VERSION 5.7 ;
  NOWIREEXTENSIONATPIN ON ;
  DIVIDERCHAR "/" ;
  BUSBITCHARS "[]" ;
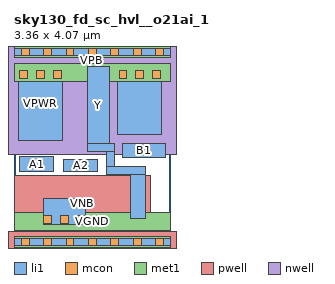
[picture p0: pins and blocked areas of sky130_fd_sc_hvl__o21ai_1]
MACRO sky130_fd_sc_hvl__o21ai_1
  CLASS BLOCK ;
  FOREIGN sky130_fd_sc_hvl__o21ai_1 ;
  ORIGIN 0.000 0.000 ;
  SIZE 3.360 BY 4.070 ;
  PIN A1
    ANTENNAGATEAREA 1.125000 ;
    PORT
      LAYER li1 ;
        RECT 0.125 1.505 0.855 1.835 ;
    END
  END A1
  PIN A2
    ANTENNAGATEAREA 1.125000 ;
    PORT
      LAYER li1 ;
        RECT 1.065 1.505 1.795 1.760 ;
    END
  END A2
  PIN B1
    ANTENNAGATEAREA 1.125000 ;
    PORT
      LAYER li1 ;
        RECT 2.325 1.805 3.235 2.120 ;
    END
  END B1
  PIN VGND
    USE GROUND ;
    PORT
      LAYER li1 ;
        RECT 0.640 0.365 1.530 0.925 ;
      LAYER mcon ;
        RECT 0.640 0.395 0.810 0.565 ;
        RECT 1.000 0.395 1.170 0.565 ;
        RECT 1.360 0.395 1.530 0.565 ;
      LAYER met1 ;
        RECT 0.000 0.255 3.360 0.625 ;
    END
  END VGND
  PIN VNB
    ANTENNADIFFAREA 0.571200 ;
    PORT
      LAYER pwell ;
        RECT 0.020 0.215 2.930 1.415 ;
        RECT -0.130 -0.215 3.490 0.215 ;
      LAYER li1 ;
        RECT 0.000 -0.085 3.360 0.085 ;
      LAYER mcon ;
        RECT 0.155 -0.085 0.325 0.085 ;
        RECT 0.635 -0.085 0.805 0.085 ;
        RECT 1.115 -0.085 1.285 0.085 ;
        RECT 1.595 -0.085 1.765 0.085 ;
        RECT 2.075 -0.085 2.245 0.085 ;
        RECT 2.555 -0.085 2.725 0.085 ;
        RECT 3.035 -0.085 3.205 0.085 ;
      LAYER met1 ;
        RECT 0.000 -0.115 3.360 0.115 ;
    END
  END VNB
  PIN VPB
    ANTENNADIFFAREA 0.571200 ;
    PORT
      LAYER nwell ;
        RECT -0.330 1.885 3.690 4.485 ;
      LAYER li1 ;
        RECT 0.000 3.985 3.360 4.155 ;
      LAYER mcon ;
        RECT 0.155 3.985 0.325 4.155 ;
        RECT 0.635 3.985 0.805 4.155 ;
        RECT 1.115 3.985 1.285 4.155 ;
        RECT 1.595 3.985 1.765 4.155 ;
        RECT 2.075 3.985 2.245 4.155 ;
        RECT 2.555 3.985 2.725 4.155 ;
        RECT 3.035 3.985 3.205 4.155 ;
      LAYER met1 ;
        RECT 0.000 3.955 3.360 4.185 ;
    END
  END VPB
  PIN VPWR
    USE POWER ;
    PORT
      LAYER li1 ;
        RECT 0.090 2.175 1.040 3.755 ;
        RECT 2.220 2.300 3.170 3.755 ;
      LAYER mcon ;
        RECT 0.120 3.505 0.290 3.675 ;
        RECT 0.480 3.505 0.650 3.675 ;
        RECT 0.840 3.505 1.010 3.675 ;
        RECT 2.250 3.505 2.420 3.675 ;
        RECT 2.610 3.505 2.780 3.675 ;
        RECT 2.970 3.505 3.140 3.675 ;
      LAYER met1 ;
        RECT 0.000 3.445 3.360 3.815 ;
    END
  END VPWR
  PIN Y
    ANTENNADIFFAREA 0.633750 ;
    PORT
      LAYER li1 ;
        RECT 1.565 2.110 2.040 3.755 ;
        RECT 1.565 1.940 2.145 2.110 ;
        RECT 1.975 1.625 2.145 1.940 ;
        RECT 1.975 1.455 2.820 1.625 ;
        RECT 2.490 0.495 2.820 1.455 ;
    END
  END Y
  OBS
      LAYER li1 ;
        RECT 0.130 1.275 0.460 1.325 ;
        RECT 0.130 1.105 2.040 1.275 ;
        RECT 0.130 0.495 0.460 1.105 ;
        RECT 1.710 0.495 2.040 1.105 ;
  END
END sky130_fd_sc_hvl__o21ai_1
END LIBRARY

